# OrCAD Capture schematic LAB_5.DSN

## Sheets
1 Exp7: size A
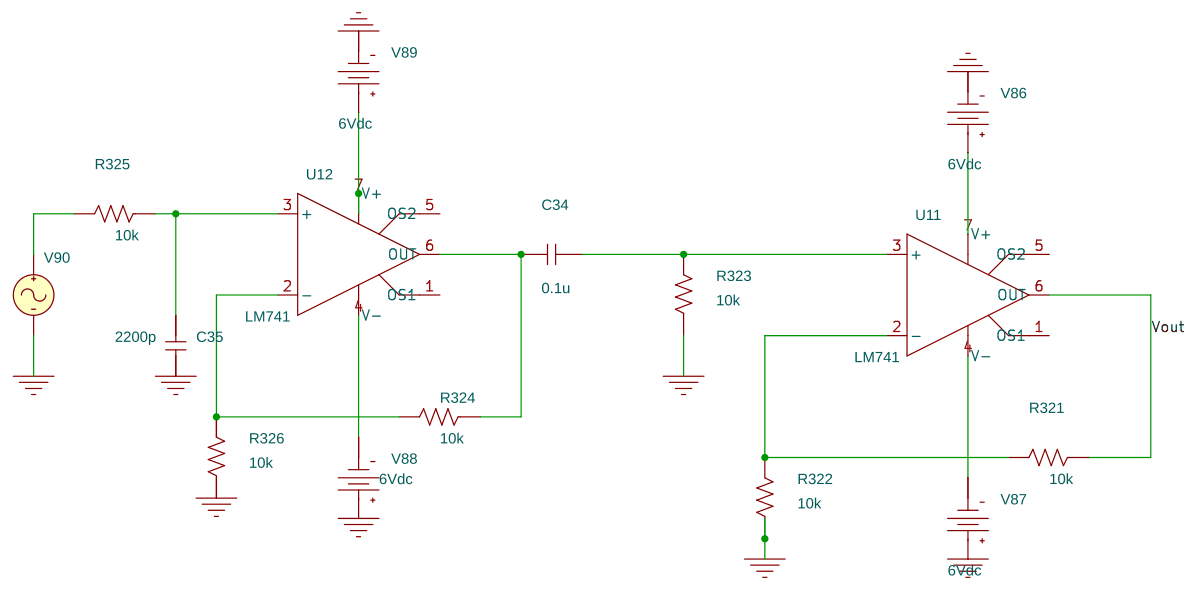
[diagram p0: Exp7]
2 Exp6: size A
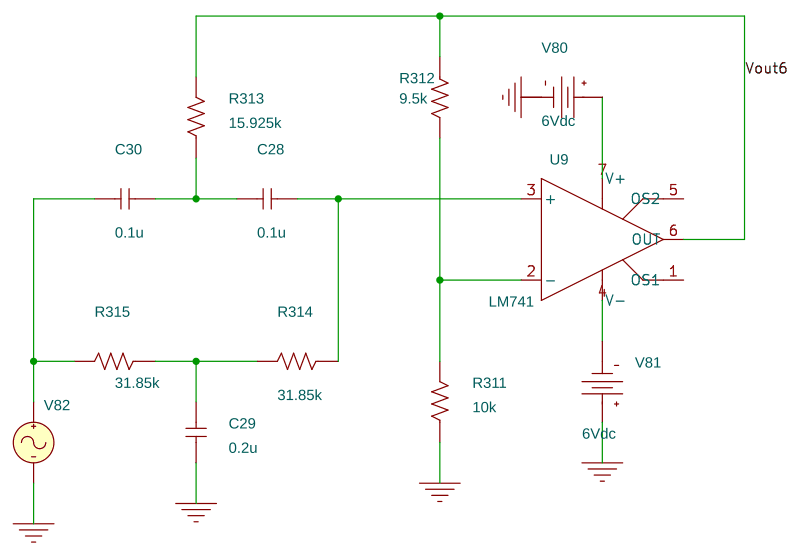
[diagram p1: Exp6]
3 Exp5: size A
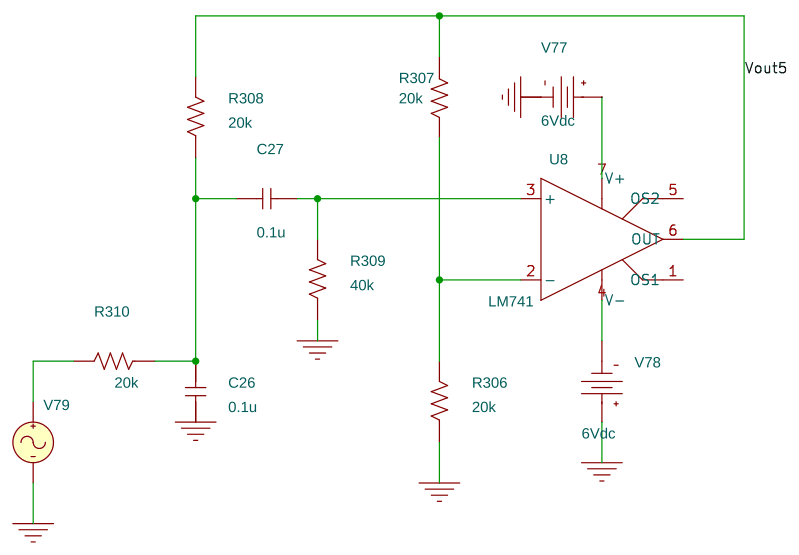
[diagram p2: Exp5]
4 Exp4: size A
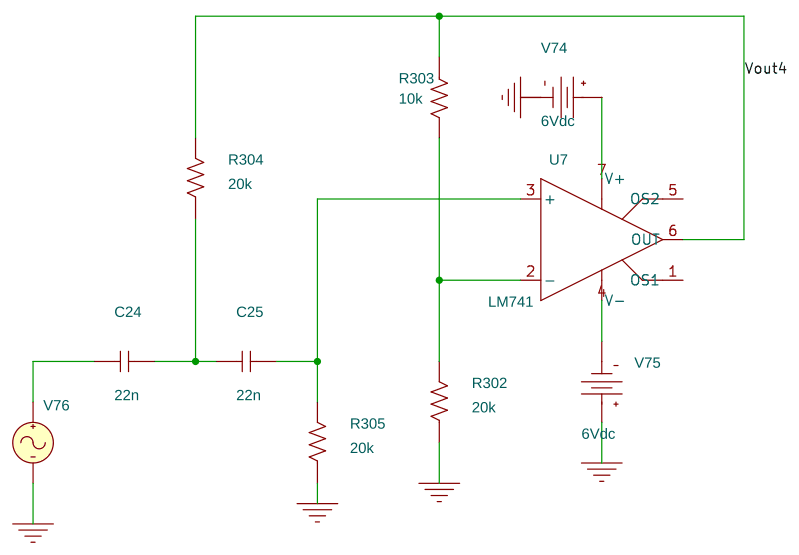
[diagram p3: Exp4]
5 Exp3: size A
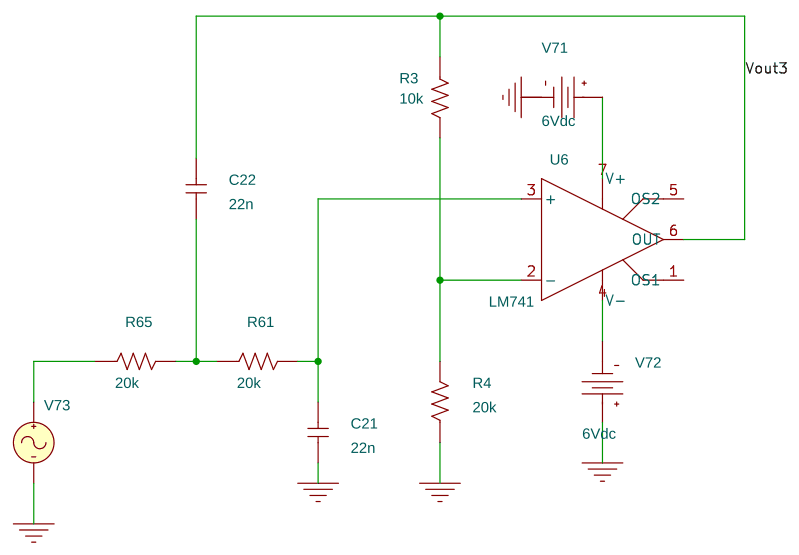
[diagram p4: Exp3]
6 Exp2: size A
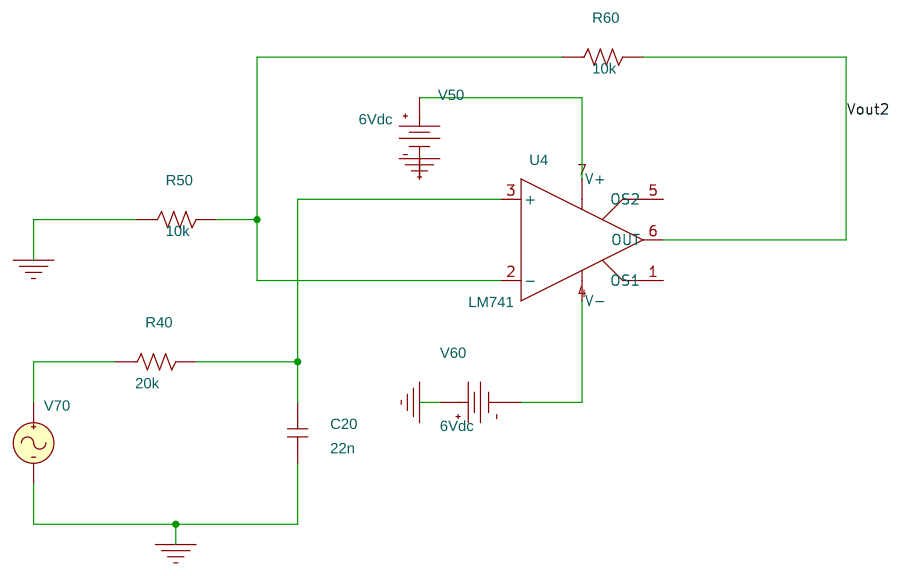
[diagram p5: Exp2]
7 Exp1: size A

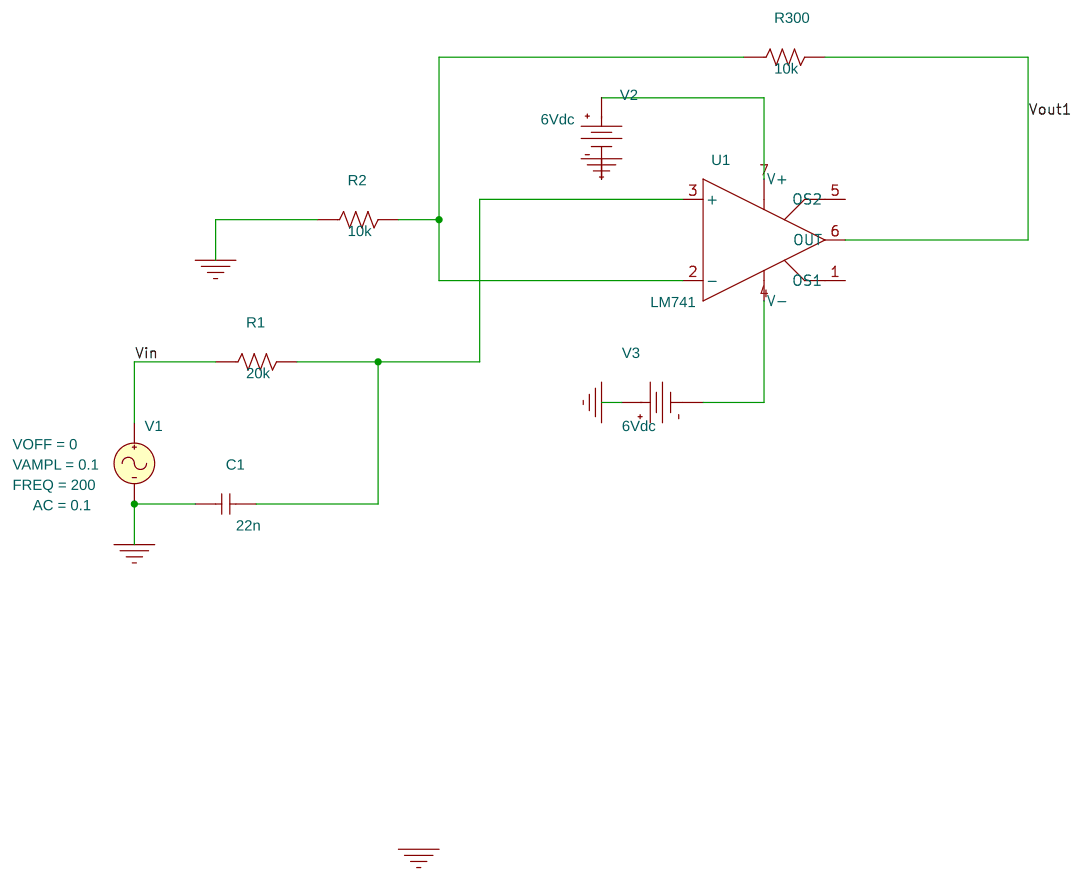
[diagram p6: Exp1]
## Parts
sheet Exp1
C1  22n  [RAD/CK05]
R1  20k  [AX/RC05]
R2  10k  [AX/RC05]
R300  10k  [AX/RC05]
U1  LM741  [DIP.100/8/W.300/L.450]
V1  VSIN
V2  VDC
V3  VDC
sheet Exp2
C20  22n  [RAD/CK05]
R40  20k  [AX/RC05]
R50  10k  [AX/RC05]
R60  10k  [AX/RC05]
U4  LM741  [DIP.100/8/W.300/L.450]
V50  VDC
V60  VDC
V70  VAC
sheet Exp3
C21  22n  [RAD/CK05]
C22  22n  [RAD/CK05]
R3  10k  [AX/RC05]
R4  20k  [AX/RC05]
R61  20k  [AX/RC05]
R65  20k  [AX/RC05]
U6  LM741  [DIP.100/8/W.300/L.450]
V71  VDC
V72  VDC
V73  VAC
sheet Exp4
C24  22n  [RAD/CK05]
C25  22n  [RAD/CK05]
R302  20k  [AX/RC05]
R303  10k  [AX/RC05]
R304  20k  [AX/RC05]
R305  20k  [AX/RC05]
U7  LM741  [DIP.100/8/W.300/L.450]
V74  VDC
V75  VDC
V76  VAC
sheet Exp5
C26  0.1u  [RAD/CK05]
C27  0.1u  [RAD/CK05]
R306  20k  [AX/RC05]
R307  20k  [AX/RC05]
R308  20k  [AX/RC05]
R309  40k  [AX/RC05]
R310  20k  [AX/RC05]
U8  LM741  [DIP.100/8/W.300/L.450]
V77  VDC
V78  VDC
V79  VAC
sheet Exp6
C28  0.1u  [RAD/CK05]
C29  0.2u  [RAD/CK05]
C30  0.1u  [RAD/CK05]
R311  10k  [AX/RC05]
R312  9.5k  [AX/RC05]
R313  15.925k  [AX/RC05]
R314  31.85k  [AX/RC05]
R315  31.85k  [AX/RC05]
U9  LM741  [DIP.100/8/W.300/L.450]
V80  VDC
V81  VDC
V82  VAC
sheet Exp7
C34  0.1u  [RAD/CK05]
C35  2200p  [RAD/CK05]
R321  10k  [AX/RC05]
R322  10k  [AX/RC05]
R323  10k  [AX/RC05]
R324  10k  [AX/RC05]
R325  10k  [AX/RC05]
R326  10k  [AX/RC05]
U11  LM741  [DIP.100/8/W.300/L.450]
U12  LM741  [DIP.100/8/W.300/L.450]
V86  VDC
V87  VDC
V88  VDC
V89  VDC
V90  VAC

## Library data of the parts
C1 C20-C22 C24-C30 C34 C35 = C
R1-R4 R40 R50 R60 R61 R65 R300 R302-R315 R321-R326 = R
U1 U4 U6-U9 U11 U12 = LM741
V1 = VSIN: AC: 0.1; FREQ: 200; VAMPL: 0.1; VOFF: 0
V2 V3 V50 V60 V71 V72 V74 V75 V77 V78 V80 V81 V86-V89 = VDC: DC: 6Vdc
V70 V73 V76 V79 V82 V90 = VAC

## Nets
Vin: R1.1 V1.1(+)
0: C1.1 C20.1 C21.1 C26.1 C29.1 C35.2 R2.1 R4.1 R50.1 R302.1 R305.1 R306.1 R309.1 R311.1 R322.1 R323.1 R326.1 V1.2(-) V2.1(-) V3.0(+) V50.1(-) V60.0(+) V70.2(-) V71.1(-) V72.0(+) V73.2(-) V74.1(-) V75.0(+) V76.2(-) V77.1(-) V78.0(+) V79.2(-) V80.1(-) V81.0(+) V82.2(-) V86.1(-) V87.0(+) V88.0(+) V89.1(-) V90.2(-)
Vout: R321.1 U11.6(OUT)
Vout1: R300.2 U1.6(OUT)
Vout2: R60.2 U4.6(OUT)
Vout3: C22.1 R3.1 U6.6(OUT)
Vout4: R303.1 R304.2 U7.6(OUT)
Vout5: R307.1 R308.2 U8.6(OUT)
Vout6: R312.1 R313.2 U9.6(OUT)
N00351: C1.2 R1.2 U1.3(+)
N00528: R2.2 R300.1 U1.2(-)
N00694: U1.7(V+) V2.0(+)
N01021: U1.4(V-) V3.1(-)
N01831: C20.2 R40.2 U4.3(+)
N01899: R50.2 R60.1 U4.2(-)
N01951: U4.7(V+) V50.0(+)
N01979: U4.4(V-) V60.1(-)
N02626: R40.1 V70.1(+)
N03292: U6.7(V+) V71.0(+)
N03320: U6.4(V-) V72.1(-)
N03386: R65.1 V73.1(+)
N03629: R3.2 R4.2 U6.2(-)
N03840: C22.2 R61.1 R65.2
N04149: C21.2 R61.2 U6.3(+)
N05804: U7.7(V+) V74.0(+)
N05816: U7.4(V-) V75.1(-)
N05834: C24.1 V76.1(+)
N05838: R302.2 R303.2 U7.2(-)
N05902: C24.2 C25.1 R304.1
N05936: C25.2 R305.2 U7.3(+)
N06836: U8.7(V+) V77.0(+)
N06848: U8.4(V-) V78.1(-)
N06866: R310.2 V79.1(+)
N06870: R306.2 R307.2 U8.2(-)
N06914: C26.2 C27.1 R308.1 R310.1
N06936: C27.2 R309.2 U8.3(+)
N07919: U9.7(V+) V80.0(+)
N07931: U9.4(V-) V81.1(-)
N07949: C30.2 R315.2 V82.1(+)
N07953: R311.2 R312.2 U9.2(-)
N07997: C29.2 R314.2 R315.1
N08005: C28.1 C30.1 R313.1
N08015: C28.2 R314.1 U9.3(+)
N10314: U11.7(V+) V86.0(+)
N10408: U11.4(V-) V87.1(-)
N10623: R321.2 R322.2 U11.2(-)
N10735: C34.2 R324.1 U12.6(OUT)
N10739: C34.1 R323.2 U11.3(+)
N10909: U12.4(V-) V88.1(-)
N10981: U12.7(V+) V89.0(+)
N11126: R324.2 R326.2 U12.2(-)
N11259: R325.2 V90.1(+)
N11597: C35.1 R325.1 U12.3(+)

Not connected (* = marked no-connect by the designer): U1 1(OS1) 5(OS2); U4 1(OS1) 5(OS2); U6 1(OS1) 5(OS2); U7 1(OS1) 5(OS2); U8 1(OS1) 5(OS2); U9 1(OS1) 5(OS2); U11 1(OS1) 5(OS2); U12 1(OS1) 5(OS2)
